VERSION 5.7 ;
BUSBITCHARS "[]" ;
DIVIDERCHAR "/" ;

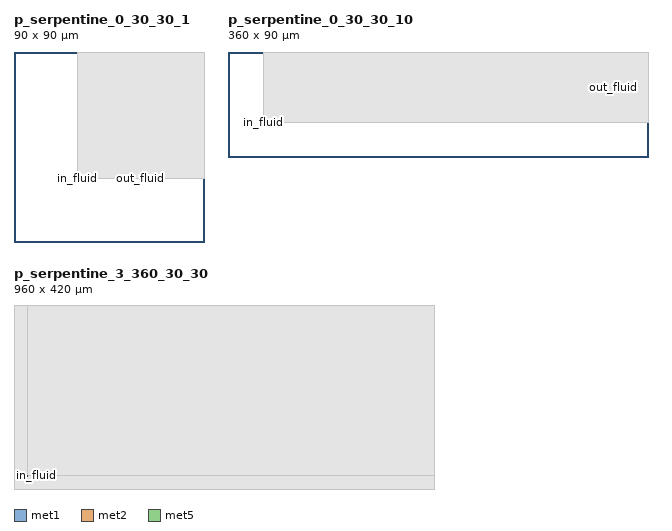
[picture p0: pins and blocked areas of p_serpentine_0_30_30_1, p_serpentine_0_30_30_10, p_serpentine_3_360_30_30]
MACRO p_serpentine_0_30_30_1
  CLASS CORE ;
  ORIGIN  0 0 ;
  FOREIGN p_serpentine_0_30_30_1 0 0 ;
  SIZE 90 BY 90 ;
  SYMMETRY X Y ;
  SITE CoreSite ;
  PIN in_fluid
    DIRECTION INPUT ;
    USE SIGNAL ;
    PORT
      LAYER met1 ;
        RECT 29.5 29.5 30.5 30.5 ;
    END
  END in_fluid
  PIN out_fluid
    DIRECTION OUTPUT ;
    USE SIGNAL ;
    PORT
      LAYER met1 ;
        RECT 59.5 29.5 60.5 30.5 ;
    END
  END out_fluid
  OBS
    LAYER met1 ;
      RECT 30 30 90 90 ;
  END
  PROPERTY CatenaDesignType "deviceLevel" ;
END p_serpentine_0_30_30_1

MACRO p_serpentine_0_30_30_10
  CLASS CORE ;
  ORIGIN  0 0 ;
  FOREIGN p_serpentine_0_30_30_10 0 0 ;
  SIZE 360 BY 90 ;
  SYMMETRY X Y ;
  SITE CoreSite ;
  PIN in_fluid
    DIRECTION INPUT ;
    USE SIGNAL ;
    PORT
      LAYER met1 ;
        RECT 29.5 29.5 30.5 30.5 ;
    END
  END in_fluid
  PIN out_fluid
    DIRECTION OUTPUT ;
    USE SIGNAL ;
    PORT
      LAYER met1 ;
        RECT 329.5 59.5 330.5 60.5 ;
    END
  END out_fluid
  OBS
    LAYER met1 ;
      RECT 30 30 360 90 ;
  END
  PROPERTY CatenaDesignType "deviceLevel" ;
END p_serpentine_0_30_30_10

MACRO p_serpentine_3_360_30_30
  CLASS CORE ;
  ORIGIN  0 0 ;
  FOREIGN p_serpentine_3_360_30_30 0 0 ;
  SIZE 960 BY 420 ;
  SYMMETRY X Y ;
  SITE CoreSite ;
  PIN in_fluid
    DIRECTION INPUT ;
    USE SIGNAL ;
    PORT
      LAYER met2 ;
        RECT 29.5 29.5 30.5 30.5 ;
    END
  END in_fluid
  PIN out_fluid
    DIRECTION OUTPUT ;
    USE SIGNAL ;
    PORT
      LAYER met5 ;
        RECT 29.5 29.5 30.5 30.5 ;
    END
  END out_fluid
  OBS
    LAYER met2 ;
      RECT 30 30 960 420 ;
    LAYER met3 ;
      RECT 0 0 960 420 ;
    LAYER met4 ;
      RECT 0 0 960 420 ;
    LAYER met5 ;
      RECT 30 30 960 420 ;
  END
  PROPERTY CatenaDesignType "deviceLevel" ;
END p_serpentine_3_360_30_30

